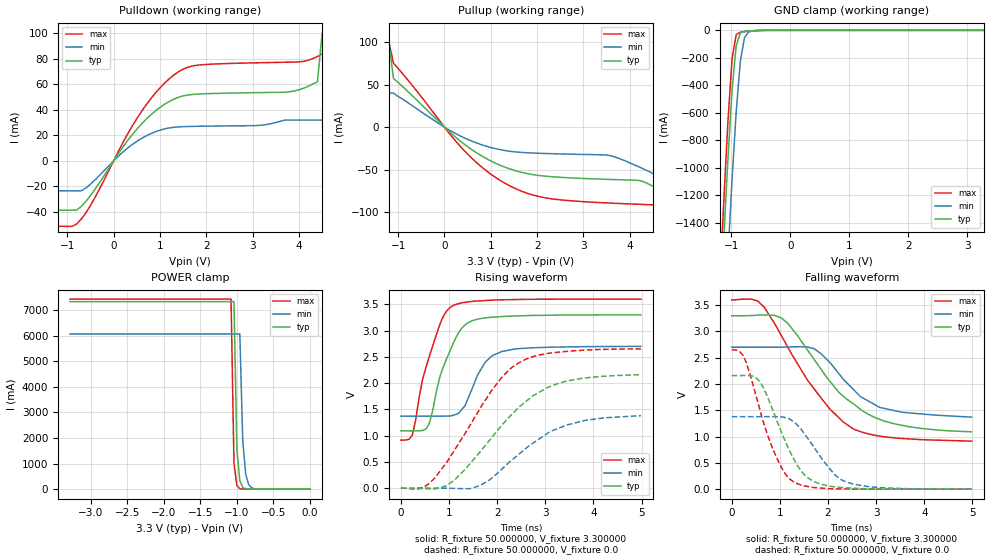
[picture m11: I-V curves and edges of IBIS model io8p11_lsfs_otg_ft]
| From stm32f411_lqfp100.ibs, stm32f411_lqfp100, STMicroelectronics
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|   Model io8p11_lsfs_otg_ft
[Model]  io8p11_lsfs_otg_ft
Model_type I/O
Polarity   Non-Inverting
Enable   Active-Low
Vinl =   0.990000V
Vinh =   2.310000V
Vmeas =  1.650000V
Cref =   30.000000pF
Rref =   100.000000M
Vref =   0.0V
C_comp   8.196500pF   7.968500pF   8.492600pF
[Temperature Range]   25.000000   0.125000k   -40.000000
[Pullup Reference]   3.300000V   2.700000V   3.600000V
[Pulldown Reference]   0.0V   0.0V   0.0V
[POWER Clamp Reference]   3.300000V   2.700000V   3.600000V
[GND Clamp Reference]   0.0V   0.0V   0.0V
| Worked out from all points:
|   slope of the pulldown table from 0 to 0.495 V, typ, clamps not added: 20.1 ohm
|   slope of the pullup table from 0 to 0.495 V, typ, clamps not added: 21.8 ohm
|   GND clamp passes 1 mA (typ) near -0.52 V on its own axis
|   POWER clamp passes 1 mA (typ) near -0.81 V on its own axis
|   rising waveform, R_fixture 50.000000, V_fixture 3.300000: 20-80 % time 466ps typ, 431ps min, 456ps max; typ from 1.09 V to 3.3 V
|   rising waveform, R_fixture 50.000000, V_fixture 0.0: 20-80 % time 1.3ns typ, 1.18ns min, 1.13ns max; typ from 0 V to 2.16 V
|   falling waveform, R_fixture 50.000000, V_fixture 3.300000: 20-80 % time 1.24ns typ, 906ps min, 1.17ns max; typ from 3.3 V to 1.09 V
|   falling waveform, R_fixture 50.000000, V_fixture 0.0: 20-80 % time 623ps typ, 666ps min, 570ps max; typ from 2.16 V to 0 V
[Pulldown]
|Voltage   I(typ)   I(min)   I(max)
-3.3V     -38.65mA   -23.43mA   -51.3mA
-800mV    -38.65mA   -23.43mA   -49.55mA
600mV     28.89mA    17.56mA    38.66mA
1.4V      49.88mA    26.66mA    69.85mA
4.1V      56.96mA    32mA       77.99mA
4.4V      62mA       32mA       81.81mA
4.5V      100mA      32mA       83.91mA
4.7V      100mA      32mA       89mA
4.8V      100mA      32mA       100mA
5.1V      100mA      32mA       100mA
5.2V      1A         1A         100mA
6.6V      1A         1A         1A
[Pullup]
|Voltage   I(typ)   I(min)   I(max)
-3.3V     1A         1A         100mA
-1.9V     1A         1A         100mA
-1.8V     100mA      1A         100mA
-1.6V     100mA      1A         100mA
-1.5V     100mA      40mA       100mA
-1.2V     100mA      40mA       100mA
-1.1V     57mA       40mA       75mA
500mV     -22.94mA   -14.36mA   -31.63mA
1.6V      -52.16mA   -29.4mA    -73.72mA
4.2V      -62.54mA   -46.6mA    -90.53mA
5.5V      -103mA     -65mA      -126.2mA
6.6V      -103mA     -65mA      -139mA
[GND_clamp]
|Voltage   I(typ)   I(min)   I(max)
-3.3V     -9.479A    -9.465A    -9.974A
-1.2V     -2.125A    -2.854A    -1.857A
-1.13V    -1.511A    -2.236A    -1.236A
-1.06V    -933.3mA   -1.641A    -660.9mA
-990mV    -433.3mA   -1.082A    -206.9mA
-920mV    -110.3mA   -591mA     -31.45mA
-850mV    -19.78mA   -226.7mA   -13.65mA
-780mV    -8.311mA   -53.93mA   -9.506mA
-710mV    -5.285mA   -11.94mA   -6.262mA
-640mV    -3.232mA   -4.282mA   -3.577mA
3.28V     0A         0A         0A
[POWER_clamp]
|Voltage   I(typ)   I(min)   I(max)
-3.28V    7.328A     6.064A     7.43A
-1.08V    7.328A     6.064A     7.43A
-1.04V    7.328A     6.064A     1.015A
-1V       1.545A     6.064A     138.6mA
-960mV    325.6mA    6.064A     18.93mA
-920mV    68.64mA    1.89A      2.585mA
-880mV    14.47mA    589mA      353uA
-840mV    3.05mA     183.6mA    105.2uA
-800mV    642.9uA    57.21mA    105.2uA
-720mV    28.59uA    5.557mA    105.2uA
0V        0A         0A         0A
[Ramp]
| variable   typ   min   max
dV/dt_r  1.26815/1.27211n   0.78786/1.10677n   1.58131/1.12071n
dV/dt_f  1.28418/1.20556n   0.74868/0.85275n   1.59074/1.16368n
R_load = 50.000000
[Rising Waveform]
R_fixture= 50.000000
V_fixture= 3.300000
V_fixture_min= 2.700000
V_fixture_max= 3.600000
|time   V(typ)   V(min)   V(max)
0s        1.091V     1.371V     914.8mV
240.2ps   1.091V     1.371V     1.022V
530.5ps   1.137V     1.371V     2.329V
600.6ps   1.258V     1.371V     2.536V
840.8ps   2.204V     1.37V      3.188V
1.061ns   2.702V     1.381V     3.463V
1.411ns   3.157V     1.745V     3.547V
1.742ns   3.24V      2.385V     3.572V
2.092ns   3.267V     2.601V     3.586V
4.985ns   3.3V       2.7V       3.6V
[Rising Waveform]
R_fixture= 50.000000
V_fixture= 0.0
V_fixture_min= 0.0
V_fixture_max= 0.0
|time   V(typ)   V(min)   V(max)
0s        42.13uV    18.71uV    -458.4uV
500.5ps   -7.378mV   44.79uV    34.72mV
700.7ps   -12.92mV   46.35uV    189.7mV
1.031ns   100.1mV    -1.915mV   605.3mV
1.652ns   699.6mV    54.16mV    1.529V
2.102ns   1.201V     368mV      2.118V
2.452ns   1.543V     647.8mV    2.388V
3.053ns   1.92V      1.052V     2.565V
3.443ns   2.038V     1.202V     2.604V
4.985ns   2.161V     1.379V     2.652V
[Falling Waveform]
R_fixture= 50.000000
V_fixture= 3.300000
V_fixture_min= 2.700000
V_fixture_max= 3.600000
|time   V(typ)   V(min)   V(max)
0s        3.3V       2.7V       3.6V
540.5ps   3.311V     2.7V       3.58V
680.7ps   3.315V     2.7V       3.455V
1.031ns   3.256V     2.701V     2.923V
1.712ns   2.468V     2.672V     1.908V
2.222ns   1.845V     2.202V     1.362V
2.513ns   1.634V     1.91V      1.154V
3.083ns   1.325V     1.553V     1.008V
3.924ns   1.156V     1.433V     942.3mV
4.985ns   1.091V     1.371V     914.8mV
[Falling Waveform]
R_fixture= 50.000000
V_fixture= 0.0
V_fixture_min= 0.0
V_fixture_max= 0.0
|time   V(typ)   V(min)   V(max)
0s        2.161V     1.379V     2.652V
240.2ps   2.162V     1.379V     2.54V
580.6ps   2.05V      1.379V     1.527V
930.9ps   1.319V     1.379V     606.4mV
1.111ns   913.7mV    1.361V     293.9mV
1.281ns   585.7mV    1.286V     142.3mV
1.672ns   162.8mV    844.4mV    36.22mV
2.142ns   44.11mV    269.3mV    6.408mV
2.372ns   24.46mV    140.1mV    3.553mV
4.985ns   42.13uV    18.71uV    -458.4uV
